VERSION 5.7 ;
  NOWIREEXTENSIONATPIN ON ;
  DIVIDERCHAR "/" ;
  BUSBITCHARS "[]" ;
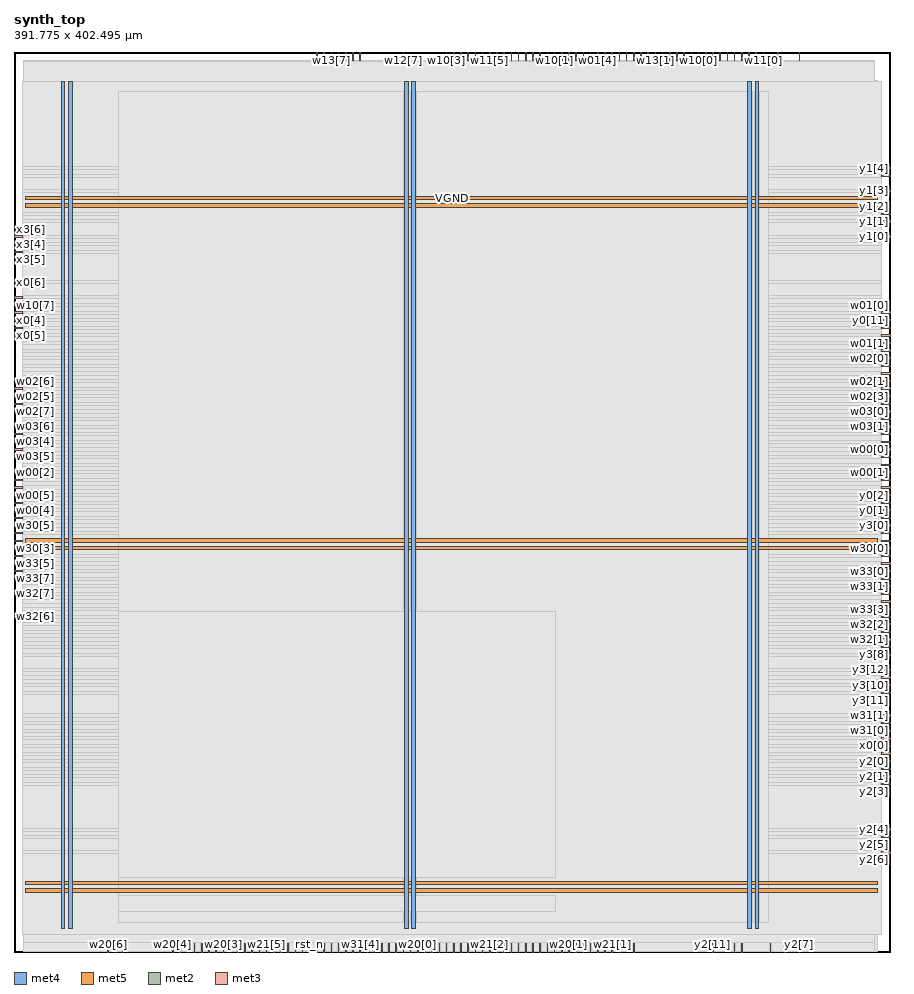
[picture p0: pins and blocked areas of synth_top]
MACRO synth_top
  CLASS BLOCK ;
  FOREIGN synth_top ;
  ORIGIN 0.000 0.000 ;
  SIZE 391.775 BY 402.495 ;
  PIN VGND
    DIRECTION INOUT ;
    USE GROUND ;
    PORT
      LAYER met4 ;
        RECT 24.340 10.640 25.940 389.200 ;
    END
    PORT
      LAYER met4 ;
        RECT 177.940 10.640 179.540 389.200 ;
    END
    PORT
      LAYER met4 ;
        RECT 331.540 10.640 333.140 389.200 ;
    END
    PORT
      LAYER met5 ;
        RECT 5.280 30.030 386.180 31.630 ;
    END
    PORT
      LAYER met5 ;
        RECT 5.280 183.210 386.180 184.810 ;
    END
    PORT
      LAYER met5 ;
        RECT 5.280 336.390 386.180 337.990 ;
    END
  END VGND
  PIN VPWR
    DIRECTION INOUT ;
    USE POWER ;
    PORT
      LAYER met4 ;
        RECT 21.040 10.640 22.640 389.200 ;
    END
    PORT
      LAYER met4 ;
        RECT 174.640 10.640 176.240 389.200 ;
    END
    PORT
      LAYER met4 ;
        RECT 328.240 10.640 329.840 389.200 ;
    END
    PORT
      LAYER met5 ;
        RECT 5.280 26.730 386.180 28.330 ;
    END
    PORT
      LAYER met5 ;
        RECT 5.280 179.910 386.180 181.510 ;
    END
    PORT
      LAYER met5 ;
        RECT 5.280 333.090 386.180 334.690 ;
    END
  END VPWR
  PIN clk
    DIRECTION INPUT ;
    USE SIGNAL ;
    ANTENNAGATEAREA 0.852000 ;
    PORT
      LAYER met2 ;
        RECT 125.670 0.000 125.950 4.000 ;
    END
  END clk
  PIN rst_n
    DIRECTION INPUT ;
    USE SIGNAL ;
    ANTENNAGATEAREA 0.159000 ;
    PORT
      LAYER met2 ;
        RECT 132.110 0.000 132.390 4.000 ;
    END
  END rst_n
  PIN w00[0]
    DIRECTION INPUT ;
    USE SIGNAL ;
    ANTENNAGATEAREA 0.196500 ;
    PORT
      LAYER met3 ;
        RECT 387.775 224.440 391.775 225.040 ;
    END
  END w00[0]
  PIN w00[1]
    DIRECTION INPUT ;
    USE SIGNAL ;
    ANTENNAGATEAREA 0.196500 ;
    PORT
      LAYER met3 ;
        RECT 387.775 214.240 391.775 214.840 ;
    END
  END w00[1]
  PIN w00[2]
    DIRECTION INPUT ;
    USE SIGNAL ;
    ANTENNAGATEAREA 0.159000 ;
    PORT
      LAYER met3 ;
        RECT 0.000 214.240 4.000 214.840 ;
    END
  END w00[2]
  PIN w00[3]
    DIRECTION INPUT ;
    USE SIGNAL ;
    ANTENNAGATEAREA 0.159000 ;
    PORT
      LAYER met3 ;
        RECT 0.000 200.640 4.000 201.240 ;
    END
  END w00[3]
  PIN w00[4]
    DIRECTION INPUT ;
    USE SIGNAL ;
    ANTENNAGATEAREA 0.159000 ;
    PORT
      LAYER met3 ;
        RECT 0.000 197.240 4.000 197.840 ;
    END
  END w00[4]
  PIN w00[5]
    DIRECTION INPUT ;
    USE SIGNAL ;
    ANTENNAGATEAREA 0.213000 ;
    PORT
      LAYER met3 ;
        RECT 0.000 204.040 4.000 204.640 ;
    END
  END w00[5]
  PIN w00[6]
    DIRECTION INPUT ;
    USE SIGNAL ;
    ANTENNAGATEAREA 0.213000 ;
    PORT
      LAYER met3 ;
        RECT 0.000 207.440 4.000 208.040 ;
    END
  END w00[6]
  PIN w00[7]
    DIRECTION INPUT ;
    USE SIGNAL ;
    ANTENNAGATEAREA 0.196500 ;
    PORT
      LAYER met3 ;
        RECT 0.000 210.840 4.000 211.440 ;
    END
  END w00[7]
  PIN w01[0]
    DIRECTION INPUT ;
    USE SIGNAL ;
    ANTENNAGATEAREA 0.213000 ;
    PORT
      LAYER met3 ;
        RECT 387.775 285.640 391.775 286.240 ;
    END
  END w01[0]
  PIN w01[1]
    DIRECTION INPUT ;
    USE SIGNAL ;
    ANTENNAGATEAREA 0.196500 ;
    PORT
      LAYER met3 ;
        RECT 387.775 272.040 391.775 272.640 ;
    END
  END w01[1]
  PIN w01[2]
    DIRECTION INPUT ;
    USE SIGNAL ;
    ANTENNAGATEAREA 0.196500 ;
    PORT
      LAYER met3 ;
        RECT 387.775 258.440 391.775 259.040 ;
    END
  END w01[2]
  PIN w01[3]
    DIRECTION INPUT ;
    USE SIGNAL ;
    ANTENNAGATEAREA 0.196500 ;
    PORT
      LAYER met2 ;
        RECT 302.770 398.495 303.050 402.495 ;
    END
  END w01[3]
  PIN w01[4]
    DIRECTION INPUT ;
    USE SIGNAL ;
    ANTENNAGATEAREA 0.196500 ;
    PORT
      LAYER met2 ;
        RECT 260.910 398.495 261.190 402.495 ;
    END
  END w01[4]
  PIN w01[5]
    DIRECTION INPUT ;
    USE SIGNAL ;
    ANTENNAGATEAREA 0.196500 ;
    PORT
      LAYER met2 ;
        RECT 277.010 398.495 277.290 402.495 ;
    END
  END w01[5]
  PIN w01[6]
    DIRECTION INPUT ;
    USE SIGNAL ;
    ANTENNAGATEAREA 0.196500 ;
    PORT
      LAYER met2 ;
        RECT 254.470 398.495 254.750 402.495 ;
    END
  END w01[6]
  PIN w01[7]
    DIRECTION INPUT ;
    USE SIGNAL ;
    ANTENNAGATEAREA 0.213000 ;
    PORT
      LAYER met2 ;
        RECT 215.830 398.495 216.110 402.495 ;
    END
  END w01[7]
  PIN w02[0]
    DIRECTION INPUT ;
    USE SIGNAL ;
    ANTENNAGATEAREA 0.213000 ;
    PORT
      LAYER met3 ;
        RECT 387.775 265.240 391.775 265.840 ;
    END
  END w02[0]
  PIN w02[1]
    DIRECTION INPUT ;
    USE SIGNAL ;
    ANTENNAGATEAREA 0.213000 ;
    PORT
      LAYER met3 ;
        RECT 387.775 255.040 391.775 255.640 ;
    END
  END w02[1]
  PIN w02[2]
    DIRECTION INPUT ;
    USE SIGNAL ;
    ANTENNAGATEAREA 0.196500 ;
    PORT
      LAYER met3 ;
        RECT 387.775 251.640 391.775 252.240 ;
    END
  END w02[2]
  PIN w02[3]
    DIRECTION INPUT ;
    USE SIGNAL ;
    ANTENNAGATEAREA 0.196500 ;
    PORT
      LAYER met3 ;
        RECT 387.775 248.240 391.775 248.840 ;
    END
  END w02[3]
  PIN w02[4]
    DIRECTION INPUT ;
    USE SIGNAL ;
    ANTENNAGATEAREA 0.213000 ;
    PORT
      LAYER met2 ;
        RECT 244.810 398.495 245.090 402.495 ;
    END
  END w02[4]
  PIN w02[5]
    DIRECTION INPUT ;
    USE SIGNAL ;
    ANTENNAGATEAREA 0.213000 ;
    PORT
      LAYER met3 ;
        RECT 0.000 248.240 4.000 248.840 ;
    END
  END w02[5]
  PIN w02[6]
    DIRECTION INPUT ;
    USE SIGNAL ;
    ANTENNAGATEAREA 0.159000 ;
    PORT
      LAYER met3 ;
        RECT 0.000 251.640 4.000 252.240 ;
    END
  END w02[6]
  PIN w02[7]
    DIRECTION INPUT ;
    USE SIGNAL ;
    ANTENNAGATEAREA 0.213000 ;
    PORT
      LAYER met3 ;
        RECT 0.000 244.840 4.000 245.440 ;
    END
  END w02[7]
  PIN w03[0]
    DIRECTION INPUT ;
    USE SIGNAL ;
    ANTENNAGATEAREA 0.213000 ;
    PORT
      LAYER met3 ;
        RECT 387.775 241.440 391.775 242.040 ;
    END
  END w03[0]
  PIN w03[1]
    DIRECTION INPUT ;
    USE SIGNAL ;
    ANTENNAGATEAREA 0.196500 ;
    PORT
      LAYER met3 ;
        RECT 387.775 238.040 391.775 238.640 ;
    END
  END w03[1]
  PIN w03[2]
    DIRECTION INPUT ;
    USE SIGNAL ;
    ANTENNAGATEAREA 0.196500 ;
    PORT
      LAYER met3 ;
        RECT 387.775 234.640 391.775 235.240 ;
    END
  END w03[2]
  PIN w03[3]
    DIRECTION INPUT ;
    USE SIGNAL ;
    ANTENNAGATEAREA 0.159000 ;
    PORT
      LAYER met3 ;
        RECT 387.775 227.840 391.775 228.440 ;
    END
  END w03[3]
  PIN w03[4]
    DIRECTION INPUT ;
    USE SIGNAL ;
    ANTENNAGATEAREA 0.213000 ;
    PORT
      LAYER met3 ;
        RECT 0.000 227.840 4.000 228.440 ;
    END
  END w03[4]
  PIN w03[5]
    DIRECTION INPUT ;
    USE SIGNAL ;
    ANTENNAGATEAREA 0.213000 ;
    PORT
      LAYER met3 ;
        RECT 0.000 224.440 4.000 225.040 ;
    END
  END w03[5]
  PIN w03[6]
    DIRECTION INPUT ;
    USE SIGNAL ;
    ANTENNAGATEAREA 0.213000 ;
    PORT
      LAYER met3 ;
        RECT 0.000 231.240 4.000 231.840 ;
    END
  END w03[6]
  PIN w03[7]
    DIRECTION INPUT ;
    USE SIGNAL ;
    ANTENNAGATEAREA 0.126000 ;
    PORT
      LAYER met3 ;
        RECT 0.000 221.040 4.000 221.640 ;
    END
  END w03[7]
  PIN w10[0]
    DIRECTION INPUT ;
    USE SIGNAL ;
    ANTENNAGATEAREA 0.196500 ;
    PORT
      LAYER met2 ;
        RECT 305.990 398.495 306.270 402.495 ;
    END
  END w10[0]
  PIN w10[1]
    DIRECTION INPUT ;
    USE SIGNAL ;
    ANTENNAGATEAREA 0.196500 ;
    PORT
      LAYER met2 ;
        RECT 241.590 398.495 241.870 402.495 ;
    END
  END w10[1]
  PIN w10[2]
    DIRECTION INPUT ;
    USE SIGNAL ;
    ANTENNAGATEAREA 0.213000 ;
    PORT
      LAYER met2 ;
        RECT 267.350 398.495 267.630 402.495 ;
    END
  END w10[2]
  PIN w10[3]
    DIRECTION INPUT ;
    USE SIGNAL ;
    ANTENNAGATEAREA 0.213000 ;
    PORT
      LAYER met2 ;
        RECT 193.290 398.495 193.570 402.495 ;
    END
  END w10[3]
  PIN w10[4]
    DIRECTION INPUT ;
    USE SIGNAL ;
    ANTENNAGATEAREA 0.213000 ;
    PORT
      LAYER met2 ;
        RECT 222.270 398.495 222.550 402.495 ;
    END
  END w10[4]
  PIN w10[5]
    DIRECTION INPUT ;
    USE SIGNAL ;
    ANTENNAGATEAREA 0.196500 ;
    PORT
      LAYER met2 ;
        RECT 219.050 398.495 219.330 402.495 ;
    END
  END w10[5]
  PIN w10[6]
    DIRECTION INPUT ;
    USE SIGNAL ;
    ANTENNAGATEAREA 0.213000 ;
    PORT
      LAYER met2 ;
        RECT 209.390 398.495 209.670 402.495 ;
    END
  END w10[6]
  PIN w10[7]
    DIRECTION INPUT ;
    USE SIGNAL ;
    ANTENNAGATEAREA 0.213000 ;
    PORT
      LAYER met3 ;
        RECT 0.000 289.040 4.000 289.640 ;
    END
  END w10[7]
  PIN w11[0]
    DIRECTION INPUT ;
    USE SIGNAL ;
    ANTENNAGATEAREA 0.126000 ;
    PORT
      LAYER met2 ;
        RECT 334.970 398.495 335.250 402.495 ;
    END
  END w11[0]
  PIN w11[1]
    DIRECTION INPUT ;
    USE SIGNAL ;
    ANTENNAGATEAREA 0.196500 ;
    PORT
      LAYER met2 ;
        RECT 296.330 398.495 296.610 402.495 ;
    END
  END w11[1]
  PIN w11[2]
    DIRECTION INPUT ;
    USE SIGNAL ;
    ANTENNAGATEAREA 0.196500 ;
    PORT
      LAYER met2 ;
        RECT 325.310 398.495 325.590 402.495 ;
    END
  END w11[2]
  PIN w11[3]
    DIRECTION INPUT ;
    USE SIGNAL ;
    ANTENNAGATEAREA 0.196500 ;
    PORT
      LAYER met2 ;
        RECT 299.550 398.495 299.830 402.495 ;
    END
  END w11[3]
  PIN w11[4]
    DIRECTION INPUT ;
    USE SIGNAL ;
    ANTENNAGATEAREA 0.196500 ;
    PORT
      LAYER met2 ;
        RECT 251.250 398.495 251.530 402.495 ;
    END
  END w11[4]
  PIN w11[5]
    DIRECTION INPUT ;
    USE SIGNAL ;
    ANTENNAGATEAREA 0.196500 ;
    PORT
      LAYER met2 ;
        RECT 212.610 398.495 212.890 402.495 ;
    END
  END w11[5]
  PIN w11[6]
    DIRECTION INPUT ;
    USE SIGNAL ;
    ANTENNAGATEAREA 0.196500 ;
    PORT
      LAYER met2 ;
        RECT 231.930 398.495 232.210 402.495 ;
    END
  END w11[6]
  PIN w11[7]
    DIRECTION INPUT ;
    USE SIGNAL ;
    ANTENNAGATEAREA 0.213000 ;
    PORT
      LAYER met2 ;
        RECT 228.710 398.495 228.990 402.495 ;
    END
  END w11[7]
  PIN w12[0]
    DIRECTION INPUT ;
    USE SIGNAL ;
    ANTENNAGATEAREA 0.126000 ;
    PORT
      LAYER met2 ;
        RECT 312.430 398.495 312.710 402.495 ;
    END
  END w12[0]
  PIN w12[1]
    DIRECTION INPUT ;
    USE SIGNAL ;
    ANTENNAGATEAREA 0.126000 ;
    PORT
      LAYER met2 ;
        RECT 248.030 398.495 248.310 402.495 ;
    END
  END w12[1]
  PIN w12[2]
    DIRECTION INPUT ;
    USE SIGNAL ;
    ANTENNAGATEAREA 0.196500 ;
    PORT
      LAYER met2 ;
        RECT 264.130 398.495 264.410 402.495 ;
    END
  END w12[2]
  PIN w12[3]
    DIRECTION INPUT ;
    USE SIGNAL ;
    ANTENNAGATEAREA 0.213000 ;
    PORT
      LAYER met2 ;
        RECT 270.570 398.495 270.850 402.495 ;
    END
  END w12[3]
  PIN w12[4]
    DIRECTION INPUT ;
    USE SIGNAL ;
    ANTENNAGATEAREA 0.213000 ;
    PORT
      LAYER met2 ;
        RECT 257.690 398.495 257.970 402.495 ;
    END
  END w12[4]
  PIN w12[5]
    DIRECTION INPUT ;
    USE SIGNAL ;
    ANTENNAGATEAREA 0.196500 ;
    PORT
      LAYER met2 ;
        RECT 199.730 398.495 200.010 402.495 ;
    END
  END w12[5]
  PIN w12[6]
    DIRECTION INPUT ;
    USE SIGNAL ;
    ANTENNAGATEAREA 0.196500 ;
    PORT
      LAYER met2 ;
        RECT 225.490 398.495 225.770 402.495 ;
    END
  END w12[6]
  PIN w12[7]
    DIRECTION INPUT ;
    USE SIGNAL ;
    ANTENNAGATEAREA 0.196500 ;
    PORT
      LAYER met2 ;
        RECT 173.970 398.495 174.250 402.495 ;
    END
  END w12[7]
  PIN w13[0]
    DIRECTION INPUT ;
    USE SIGNAL ;
    ANTENNAGATEAREA 0.213000 ;
    PORT
      LAYER met2 ;
        RECT 289.890 398.495 290.170 402.495 ;
    END
  END w13[0]
  PIN w13[1]
    DIRECTION INPUT ;
    USE SIGNAL ;
    ANTENNAGATEAREA 0.196500 ;
    PORT
      LAYER met2 ;
        RECT 286.670 398.495 286.950 402.495 ;
    END
  END w13[1]
  PIN w13[2]
    DIRECTION INPUT ;
    USE SIGNAL ;
    ANTENNAGATEAREA 0.196500 ;
    PORT
      LAYER met2 ;
        RECT 202.950 398.495 203.230 402.495 ;
    END
  END w13[2]
  PIN w13[3]
    DIRECTION INPUT ;
    USE SIGNAL ;
    ANTENNAGATEAREA 0.213000 ;
    PORT
      LAYER met2 ;
        RECT 283.450 398.495 283.730 402.495 ;
    END
  END w13[3]
  PIN w13[4]
    DIRECTION INPUT ;
    USE SIGNAL ;
    ANTENNAGATEAREA 0.196500 ;
    PORT
      LAYER met2 ;
        RECT 273.790 398.495 274.070 402.495 ;
    END
  END w13[4]
  PIN w13[5]
    DIRECTION INPUT ;
    USE SIGNAL ;
    ANTENNAGATEAREA 0.196500 ;
    PORT
      LAYER met2 ;
        RECT 235.150 398.495 235.430 402.495 ;
    END
  END w13[5]
  PIN w13[6]
    DIRECTION INPUT ;
    USE SIGNAL ;
    ANTENNAGATEAREA 0.213000 ;
    PORT
      LAYER met2 ;
        RECT 196.510 398.495 196.790 402.495 ;
    END
  END w13[6]
  PIN w13[7]
    DIRECTION INPUT ;
    USE SIGNAL ;
    ANTENNAGATEAREA 0.213000 ;
    PORT
      LAYER met2 ;
        RECT 141.770 398.495 142.050 402.495 ;
    END
  END w13[7]
  PIN w20[0]
    DIRECTION INPUT ;
    USE SIGNAL ;
    ANTENNAGATEAREA 0.213000 ;
    PORT
      LAYER met2 ;
        RECT 180.410 0.000 180.690 4.000 ;
    END
  END w20[0]
  PIN w20[1]
    DIRECTION INPUT ;
    USE SIGNAL ;
    ANTENNAGATEAREA 0.196500 ;
    PORT
      LAYER met2 ;
        RECT 248.030 0.000 248.310 4.000 ;
    END
  END w20[1]
  PIN w20[2]
    DIRECTION INPUT ;
    USE SIGNAL ;
    ANTENNAGATEAREA 0.213000 ;
    PORT
      LAYER met2 ;
        RECT 119.230 0.000 119.510 4.000 ;
    END
  END w20[2]
  PIN w20[3]
    DIRECTION INPUT ;
    USE SIGNAL ;
    ANTENNAGATEAREA 0.159000 ;
    PORT
      LAYER met2 ;
        RECT 93.470 0.000 93.750 4.000 ;
    END
  END w20[3]
  PIN w20[4]
    DIRECTION INPUT ;
    USE SIGNAL ;
    ANTENNAGATEAREA 0.213000 ;
    PORT
      LAYER met2 ;
        RECT 70.930 0.000 71.210 4.000 ;
    END
  END w20[4]
  PIN w20[5]
    DIRECTION INPUT ;
    USE SIGNAL ;
    ANTENNAGATEAREA 0.213000 ;
    PORT
      LAYER met2 ;
        RECT 45.170 0.000 45.450 4.000 ;
    END
  END w20[5]
  PIN w20[6]
    DIRECTION INPUT ;
    USE SIGNAL ;
    ANTENNAGATEAREA 0.159000 ;
    PORT
      LAYER met2 ;
        RECT 41.950 0.000 42.230 4.000 ;
    END
  END w20[6]
  PIN w20[7]
    DIRECTION INPUT ;
    USE SIGNAL ;
    ANTENNAGATEAREA 0.213000 ;
    PORT
      LAYER met2 ;
        RECT 48.390 0.000 48.670 4.000 ;
    END
  END w20[7]
  PIN w21[0]
    DIRECTION INPUT ;
    USE SIGNAL ;
    ANTENNAGATEAREA 0.213000 ;
    PORT
      LAYER met2 ;
        RECT 277.010 0.000 277.290 4.000 ;
    END
  END w21[0]
  PIN w21[1]
    DIRECTION INPUT ;
    USE SIGNAL ;
    ANTENNAGATEAREA 0.196500 ;
    PORT
      LAYER met2 ;
        RECT 267.350 0.000 267.630 4.000 ;
    END
  END w21[1]
  PIN w21[2]
    DIRECTION INPUT ;
    USE SIGNAL ;
    ANTENNAGATEAREA 0.213000 ;
    PORT
      LAYER met2 ;
        RECT 212.610 0.000 212.890 4.000 ;
    END
  END w21[2]
  PIN w21[3]
    DIRECTION INPUT ;
    USE SIGNAL ;
    ANTENNAGATEAREA 0.196500 ;
    PORT
      LAYER met2 ;
        RECT 173.970 0.000 174.250 4.000 ;
    END
  END w21[3]
  PIN w21[4]
    DIRECTION INPUT ;
    USE SIGNAL ;
    ANTENNAGATEAREA 0.196500 ;
    PORT
      LAYER met2 ;
        RECT 141.770 0.000 142.050 4.000 ;
    END
  END w21[4]
  PIN w21[5]
    DIRECTION INPUT ;
    USE SIGNAL ;
    ANTENNAGATEAREA 0.196500 ;
    PORT
      LAYER met2 ;
        RECT 112.790 0.000 113.070 4.000 ;
    END
  END w21[5]
  PIN w21[6]
    DIRECTION INPUT ;
    USE SIGNAL ;
    ANTENNAGATEAREA 0.196500 ;
    PORT
      LAYER met2 ;
        RECT 99.910 0.000 100.190 4.000 ;
    END
  END w21[6]
  PIN w21[7]
    DIRECTION INPUT ;
    USE SIGNAL ;
    ANTENNAGATEAREA 0.196500 ;
    PORT
      LAYER met2 ;
        RECT 116.010 0.000 116.290 4.000 ;
    END
  END w21[7]
  PIN w22[0]
    DIRECTION INPUT ;
    USE SIGNAL ;
    ANTENNAGATEAREA 0.213000 ;
    PORT
      LAYER met2 ;
        RECT 235.150 0.000 235.430 4.000 ;
    END
  END w22[0]
  PIN w22[1]
    DIRECTION INPUT ;
    USE SIGNAL ;
    ANTENNAGATEAREA 0.213000 ;
    PORT
      LAYER met2 ;
        RECT 206.170 0.000 206.450 4.000 ;
    END
  END w22[1]
  PIN w22[2]
    DIRECTION INPUT ;
    USE SIGNAL ;
    ANTENNAGATEAREA 0.196500 ;
    PORT
      LAYER met2 ;
        RECT 251.250 0.000 251.530 4.000 ;
    END
  END w22[2]
  PIN w22[3]
    DIRECTION INPUT ;
    USE SIGNAL ;
    ANTENNAGATEAREA 0.196500 ;
    PORT
      LAYER met2 ;
        RECT 144.990 0.000 145.270 4.000 ;
    END
  END w22[3]
  PIN w22[4]
    DIRECTION INPUT ;
    USE SIGNAL ;
    ANTENNAGATEAREA 0.196500 ;
    PORT
      LAYER met2 ;
        RECT 231.930 0.000 232.210 4.000 ;
    END
  END w22[4]
  PIN w22[5]
    DIRECTION INPUT ;
    USE SIGNAL ;
    ANTENNAGATEAREA 0.126000 ;
    PORT
      LAYER met2 ;
        RECT 106.350 0.000 106.630 4.000 ;
    END
  END w22[5]
  PIN w22[6]
    DIRECTION INPUT ;
    USE SIGNAL ;
    ANTENNAGATEAREA 0.196500 ;
    PORT
      LAYER met2 ;
        RECT 87.030 0.000 87.310 4.000 ;
    END
  END w22[6]
  PIN w22[7]
    DIRECTION INPUT ;
    USE SIGNAL ;
    ANTENNAGATEAREA 0.196500 ;
    PORT
      LAYER met2 ;
        RECT 77.370 0.000 77.650 4.000 ;
    END
  END w22[7]
  PIN w23[0]
    DIRECTION INPUT ;
    USE SIGNAL ;
    ANTENNAGATEAREA 0.159000 ;
    PORT
      LAYER met2 ;
        RECT 190.070 0.000 190.350 4.000 ;
    END
  END w23[0]
  PIN w23[1]
    DIRECTION INPUT ;
    USE SIGNAL ;
    ANTENNAGATEAREA 0.196500 ;
    PORT
      LAYER met2 ;
        RECT 183.630 0.000 183.910 4.000 ;
    END
  END w23[1]
  PIN w23[2]
    DIRECTION INPUT ;
    USE SIGNAL ;
    ANTENNAGATEAREA 0.126000 ;
    PORT
      LAYER met2 ;
        RECT 148.210 0.000 148.490 4.000 ;
    END
  END w23[2]
  PIN w23[3]
    DIRECTION INPUT ;
    USE SIGNAL ;
    ANTENNAGATEAREA 0.213000 ;
    PORT
      LAYER met2 ;
        RECT 128.890 0.000 129.170 4.000 ;
    END
  END w23[3]
  PIN w23[4]
    DIRECTION INPUT ;
    USE SIGNAL ;
    ANTENNAGATEAREA 0.196500 ;
    PORT
      LAYER met2 ;
        RECT 264.130 0.000 264.410 4.000 ;
    END
  END w23[4]
  PIN w23[5]
    DIRECTION INPUT ;
    USE SIGNAL ;
    ANTENNAGATEAREA 0.196500 ;
    PORT
      LAYER met2 ;
        RECT 83.810 0.000 84.090 4.000 ;
    END
  END w23[5]
  PIN w23[6]
    DIRECTION INPUT ;
    USE SIGNAL ;
    ANTENNAGATEAREA 0.126000 ;
    PORT
      LAYER met2 ;
        RECT 74.150 0.000 74.430 4.000 ;
    END
  END w23[6]
  PIN w23[7]
    DIRECTION INPUT ;
    USE SIGNAL ;
    ANTENNAGATEAREA 0.196500 ;
    PORT
      LAYER met2 ;
        RECT 80.590 0.000 80.870 4.000 ;
    END
  END w23[7]
  PIN w30[0]
    DIRECTION INPUT ;
    USE SIGNAL ;
    ANTENNAGATEAREA 0.213000 ;
    PORT
      LAYER met3 ;
        RECT 387.775 180.240 391.775 180.840 ;
    END
  END w30[0]
  PIN w30[1]
    DIRECTION INPUT ;
    USE SIGNAL ;
    ANTENNAGATEAREA 0.196500 ;
    PORT
      LAYER met3 ;
        RECT 387.775 200.640 391.775 201.240 ;
    END
  END w30[1]
  PIN w30[2]
    DIRECTION INPUT ;
    USE SIGNAL ;
    ANTENNAGATEAREA 0.213000 ;
    PORT
      LAYER met3 ;
        RECT 387.775 183.640 391.775 184.240 ;
    END
  END w30[2]
  PIN w30[3]
    DIRECTION INPUT ;
    USE SIGNAL ;
    ANTENNAGATEAREA 0.159000 ;
    PORT
      LAYER met3 ;
        RECT 0.000 180.240 4.000 180.840 ;
    END
  END w30[3]
  PIN w30[4]
    DIRECTION INPUT ;
    USE SIGNAL ;
    ANTENNAGATEAREA 0.159000 ;
    PORT
      LAYER met3 ;
        RECT 0.000 183.640 4.000 184.240 ;
    END
  END w30[4]
  PIN w30[5]
    DIRECTION INPUT ;
    USE SIGNAL ;
    ANTENNAGATEAREA 0.213000 ;
    PORT
      LAYER met3 ;
        RECT 0.000 190.440 4.000 191.040 ;
    END
  END w30[5]
  PIN w30[6]
    DIRECTION INPUT ;
    USE SIGNAL ;
    ANTENNAGATEAREA 0.159000 ;
    PORT
      LAYER met3 ;
        RECT 0.000 193.840 4.000 194.440 ;
    END
  END w30[6]
  PIN w30[7]
    DIRECTION INPUT ;
    USE SIGNAL ;
    ANTENNAGATEAREA 0.213000 ;
    PORT
      LAYER met3 ;
        RECT 0.000 187.040 4.000 187.640 ;
    END
  END w30[7]
  PIN w31[0]
    DIRECTION INPUT ;
    USE SIGNAL ;
    ANTENNAGATEAREA 0.213000 ;
    PORT
      LAYER met3 ;
        RECT 387.775 98.640 391.775 99.240 ;
    END
  END w31[0]
  PIN w31[1]
    DIRECTION INPUT ;
    USE SIGNAL ;
    ANTENNAGATEAREA 0.196500 ;
    PORT
      LAYER met3 ;
        RECT 387.775 102.040 391.775 102.640 ;
    END
  END w31[1]
  PIN w31[2]
    DIRECTION INPUT ;
    USE SIGNAL ;
    ANTENNAGATEAREA 0.196500 ;
    PORT
      LAYER met2 ;
        RECT 254.470 0.000 254.750 4.000 ;
    END
  END w31[2]
  PIN w31[3]
    DIRECTION INPUT ;
    USE SIGNAL ;
    ANTENNAGATEAREA 0.126000 ;
    PORT
      LAYER met2 ;
        RECT 209.390 0.000 209.670 4.000 ;
    END
  END w31[3]
  PIN w31[4]
    DIRECTION INPUT ;
    USE SIGNAL ;
    ANTENNAGATEAREA 0.213000 ;
    PORT
      LAYER met2 ;
        RECT 154.650 0.000 154.930 4.000 ;
    END
  END w31[4]
  PIN w31[5]
    DIRECTION INPUT ;
    USE SIGNAL ;
    ANTENNAGATEAREA 0.126000 ;
    PORT
      LAYER met2 ;
        RECT 151.430 0.000 151.710 4.000 ;
    END
  END w31[5]
  PIN w31[6]
    DIRECTION INPUT ;
    USE SIGNAL ;
    ANTENNAGATEAREA 0.213000 ;
    PORT
      LAYER met2 ;
        RECT 109.570 0.000 109.850 4.000 ;
    END
  END w31[6]
  PIN w31[7]
    DIRECTION INPUT ;
    USE SIGNAL ;
    ANTENNAGATEAREA 0.213000 ;
    PORT
      LAYER met2 ;
        RECT 122.450 0.000 122.730 4.000 ;
    END
  END w31[7]
  PIN w32[0]
    DIRECTION INPUT ;
    USE SIGNAL ;
    ANTENNAGATEAREA 0.213000 ;
    PORT
      LAYER met3 ;
        RECT 387.775 122.440 391.775 123.040 ;
    END
  END w32[0]
  PIN w32[1]
    DIRECTION INPUT ;
    USE SIGNAL ;
    ANTENNAGATEAREA 0.126000 ;
    PORT
      LAYER met3 ;
        RECT 387.775 139.440 391.775 140.040 ;
    END
  END w32[1]
  PIN w32[2]
    DIRECTION INPUT ;
    USE SIGNAL ;
    ANTENNAGATEAREA 0.213000 ;
    PORT
      LAYER met3 ;
        RECT 387.775 142.840 391.775 143.440 ;
    END
  END w32[2]
  PIN w32[3]
    DIRECTION INPUT ;
    USE SIGNAL ;
    ANTENNAGATEAREA 0.213000 ;
    PORT
      LAYER met2 ;
        RECT 170.750 0.000 171.030 4.000 ;
    END
  END w32[3]
  PIN w32[4]
    DIRECTION INPUT ;
    USE SIGNAL ;
    ANTENNAGATEAREA 0.213000 ;
    PORT
      LAYER met2 ;
        RECT 222.270 0.000 222.550 4.000 ;
    END
  END w32[4]
  PIN w32[5]
    DIRECTION INPUT ;
    USE SIGNAL ;
    ANTENNAGATEAREA 0.159000 ;
    PORT
      LAYER met2 ;
        RECT 103.130 0.000 103.410 4.000 ;
    END
  END w32[5]
  PIN w32[6]
    DIRECTION INPUT ;
    USE SIGNAL ;
    ANTENNAGATEAREA 0.213000 ;
    PORT
      LAYER met3 ;
        RECT 0.000 149.640 4.000 150.240 ;
    END
  END w32[6]
  PIN w32[7]
    DIRECTION INPUT ;
    USE SIGNAL ;
    ANTENNAGATEAREA 0.213000 ;
    PORT
      LAYER met3 ;
        RECT 0.000 159.840 4.000 160.440 ;
    END
  END w32[7]
  PIN w33[0]
    DIRECTION INPUT ;
    USE SIGNAL ;
    ANTENNAGATEAREA 0.213000 ;
    PORT
      LAYER met3 ;
        RECT 387.775 170.040 391.775 170.640 ;
    END
  END w33[0]
  PIN w33[1]
    DIRECTION INPUT ;
    USE SIGNAL ;
    ANTENNAGATEAREA 0.196500 ;
    PORT
      LAYER met3 ;
        RECT 387.775 163.240 391.775 163.840 ;
    END
  END w33[1]
  PIN w33[2]
    DIRECTION INPUT ;
    USE SIGNAL ;
    ANTENNAGATEAREA 0.196500 ;
    PORT
      LAYER met3 ;
        RECT 387.775 149.640 391.775 150.240 ;
    END
  END w33[2]
  PIN w33[3]
    DIRECTION INPUT ;
    USE SIGNAL ;
    ANTENNAGATEAREA 0.159000 ;
    PORT
      LAYER met3 ;
        RECT 387.775 153.040 391.775 153.640 ;
    END
  END w33[3]
  PIN w33[4]
    DIRECTION INPUT ;
    USE SIGNAL ;
    ANTENNAGATEAREA 0.126000 ;
    PORT
      LAYER met3 ;
        RECT 387.775 159.840 391.775 160.440 ;
    END
  END w33[4]
  PIN w33[5]
    DIRECTION INPUT ;
    USE SIGNAL ;
    ANTENNAGATEAREA 0.196500 ;
    PORT
      LAYER met3 ;
        RECT 0.000 176.840 4.000 177.440 ;
    END
  END w33[5]
  PIN w33[6]
    DIRECTION INPUT ;
    USE SIGNAL ;
    ANTENNAGATEAREA 0.196500 ;
    PORT
      LAYER met3 ;
        RECT 0.000 173.440 4.000 174.040 ;
    END
  END w33[6]
  PIN w33[7]
    DIRECTION INPUT ;
    USE SIGNAL ;
    ANTENNAGATEAREA 0.196500 ;
    PORT
      LAYER met3 ;
        RECT 0.000 170.040 4.000 170.640 ;
    END
  END w33[7]
  PIN x0[0]
    DIRECTION INPUT ;
    USE SIGNAL ;
    ANTENNAGATEAREA 0.742500 ;
    PORT
      LAYER met3 ;
        RECT 387.775 91.840 391.775 92.440 ;
    END
  END x0[0]
  PIN x0[1]
    DIRECTION INPUT ;
    USE SIGNAL ;
    ANTENNAGATEAREA 0.495000 ;
    PORT
      LAYER met2 ;
        RECT 270.570 0.000 270.850 4.000 ;
    END
  END x0[1]
  PIN x0[2]
    DIRECTION INPUT ;
    USE SIGNAL ;
    ANTENNAGATEAREA 0.213000 ;
    PORT
      LAYER met3 ;
        RECT 0.000 292.440 4.000 293.040 ;
    END
  END x0[2]
  PIN x0[3]
    DIRECTION INPUT ;
    USE SIGNAL ;
    ANTENNAGATEAREA 0.196500 ;
    PORT
      LAYER met3 ;
        RECT 0.000 285.640 4.000 286.240 ;
    END
  END x0[3]
  PIN x0[4]
    DIRECTION INPUT ;
    USE SIGNAL ;
    ANTENNAGATEAREA 0.196500 ;
    PORT
      LAYER met3 ;
        RECT 0.000 282.240 4.000 282.840 ;
    END
  END x0[4]
  PIN x0[5]
    DIRECTION INPUT ;
    USE SIGNAL ;
    ANTENNAGATEAREA 0.196500 ;
    PORT
      LAYER met3 ;
        RECT 0.000 278.840 4.000 279.440 ;
    END
  END x0[5]
  PIN x0[6]
    DIRECTION INPUT ;
    USE SIGNAL ;
    ANTENNAGATEAREA 0.126000 ;
    PORT
      LAYER met3 ;
        RECT 0.000 299.240 4.000 299.840 ;
    END
  END x0[6]
  PIN x0[7]
    DIRECTION INPUT ;
    USE SIGNAL ;
    ANTENNAGATEAREA 0.213000 ;
    PORT
      LAYER met3 ;
        RECT 0.000 275.440 4.000 276.040 ;
    END
  END x0[7]
  PIN x1[0]
    DIRECTION INPUT ;
    USE SIGNAL ;
    ANTENNAGATEAREA 0.196500 ;
    PORT
      LAYER met2 ;
        RECT 328.530 398.495 328.810 402.495 ;
    END
  END x1[0]
  PIN x1[1]
    DIRECTION INPUT ;
    USE SIGNAL ;
    ANTENNAGATEAREA 0.196500 ;
    PORT
      LAYER met2 ;
        RECT 322.090 398.495 322.370 402.495 ;
    END
  END x1[1]
  PIN x1[2]
    DIRECTION INPUT ;
    USE SIGNAL ;
    ANTENNAGATEAREA 0.196500 ;
    PORT
      LAYER met2 ;
        RECT 331.750 398.495 332.030 402.495 ;
    END
  END x1[2]
  PIN x1[3]
    DIRECTION INPUT ;
    USE SIGNAL ;
    ANTENNAGATEAREA 0.159000 ;
    PORT
      LAYER met2 ;
        RECT 167.530 0.000 167.810 4.000 ;
    END
  END x1[3]
  PIN x1[4]
    DIRECTION INPUT ;
    USE SIGNAL ;
    ANTENNAGATEAREA 0.196500 ;
    PORT
      LAYER met2 ;
        RECT 219.050 0.000 219.330 4.000 ;
    END
  END x1[4]
  PIN x1[5]
    DIRECTION INPUT ;
    USE SIGNAL ;
    ANTENNAGATEAREA 0.196500 ;
    PORT
      LAYER met2 ;
        RECT 257.690 0.000 257.970 4.000 ;
    END
  END x1[5]
  PIN x1[6]
    DIRECTION INPUT ;
    USE SIGNAL ;
    ANTENNAGATEAREA 0.196500 ;
    PORT
      LAYER met2 ;
        RECT 96.690 0.000 96.970 4.000 ;
    END
  END x1[6]
  PIN x1[7]
    DIRECTION INPUT ;
    USE SIGNAL ;
    ANTENNAGATEAREA 0.196500 ;
    PORT
      LAYER met2 ;
        RECT 196.510 0.000 196.790 4.000 ;
    END
  END x1[7]
  PIN x2[0]
    DIRECTION INPUT ;
    USE SIGNAL ;
    ANTENNAGATEAREA 0.213000 ;
    PORT
      LAYER met2 ;
        RECT 157.870 0.000 158.150 4.000 ;
    END
  END x2[0]
  PIN x2[1]
    DIRECTION INPUT ;
    USE SIGNAL ;
    ANTENNAGATEAREA 0.213000 ;
    PORT
      LAYER met2 ;
        RECT 90.250 0.000 90.530 4.000 ;
    END
  END x2[1]
  PIN x2[2]
    DIRECTION INPUT ;
    USE SIGNAL ;
    ANTENNAGATEAREA 0.196500 ;
    PORT
      LAYER met2 ;
        RECT 238.370 0.000 238.650 4.000 ;
    END
  END x2[2]
  PIN x2[3]
    DIRECTION INPUT ;
    USE SIGNAL ;
    ANTENNAGATEAREA 0.159000 ;
    PORT
      LAYER met2 ;
        RECT 215.830 0.000 216.110 4.000 ;
    END
  END x2[3]
  PIN x2[4]
    DIRECTION INPUT ;
    USE SIGNAL ;
    ANTENNAGATEAREA 0.196500 ;
    PORT
      LAYER met2 ;
        RECT 244.810 0.000 245.090 4.000 ;
    END
  END x2[4]
  PIN x2[5]
    DIRECTION INPUT ;
    USE SIGNAL ;
    ANTENNAGATEAREA 0.196500 ;
    PORT
      LAYER met2 ;
        RECT 260.910 0.000 261.190 4.000 ;
    END
  END x2[5]
  PIN x2[6]
    DIRECTION INPUT ;
    USE SIGNAL ;
    ANTENNAGATEAREA 0.196500 ;
    PORT
      LAYER met2 ;
        RECT 225.490 0.000 225.770 4.000 ;
    END
  END x2[6]
  PIN x2[7]
    DIRECTION INPUT ;
    USE SIGNAL ;
    ANTENNAGATEAREA 0.426000 ;
    PORT
      LAYER met2 ;
        RECT 228.710 0.000 228.990 4.000 ;
    END
  END x2[7]
  PIN x3[0]
    DIRECTION INPUT ;
    USE SIGNAL ;
    ANTENNAGATEAREA 0.196500 ;
    PORT
      LAYER met3 ;
        RECT 387.775 88.440 391.775 89.040 ;
    END
  END x3[0]
  PIN x3[1]
    DIRECTION INPUT ;
    USE SIGNAL ;
    ANTENNAGATEAREA 0.196500 ;
    PORT
      LAYER met3 ;
        RECT 387.775 95.240 391.775 95.840 ;
    END
  END x3[1]
  PIN x3[2]
    DIRECTION INPUT ;
    USE SIGNAL ;
    ANTENNAGATEAREA 0.213000 ;
    PORT
      LAYER met3 ;
        RECT 387.775 105.440 391.775 106.040 ;
    END
  END x3[2]
  PIN x3[3]
    DIRECTION INPUT ;
    USE SIGNAL ;
    ANTENNAGATEAREA 0.196500 ;
    PORT
      LAYER met2 ;
        RECT 241.590 0.000 241.870 4.000 ;
    END
  END x3[3]
  PIN x3[4]
    DIRECTION INPUT ;
    USE SIGNAL ;
    ANTENNAGATEAREA 0.196500 ;
    PORT
      LAYER met3 ;
        RECT 0.000 316.240 4.000 316.840 ;
    END
  END x3[4]
  PIN x3[5]
    DIRECTION INPUT ;
    USE SIGNAL ;
    ANTENNAGATEAREA 0.196500 ;
    PORT
      LAYER met3 ;
        RECT 0.000 312.840 4.000 313.440 ;
    END
  END x3[5]
  PIN x3[6]
    DIRECTION INPUT ;
    USE SIGNAL ;
    ANTENNAGATEAREA 0.213000 ;
    PORT
      LAYER met3 ;
        RECT 0.000 319.640 4.000 320.240 ;
    END
  END x3[6]
  PIN x3[7]
    DIRECTION INPUT ;
    USE SIGNAL ;
    ANTENNAGATEAREA 0.213000 ;
    PORT
      LAYER met2 ;
        RECT 138.550 0.000 138.830 4.000 ;
    END
  END x3[7]
  PIN y0[0]
    DIRECTION OUTPUT ;
    USE SIGNAL ;
    ANTENNADIFFAREA 0.445500 ;
    PORT
      LAYER met3 ;
        RECT 387.775 217.640 391.775 218.240 ;
    END
  END y0[0]
  PIN y0[10]
    DIRECTION OUTPUT ;
    USE SIGNAL ;
    ANTENNADIFFAREA 0.445500 ;
    PORT
      LAYER met3 ;
        RECT 387.775 278.840 391.775 279.440 ;
    END
  END y0[10]
  PIN y0[11]
    DIRECTION OUTPUT ;
    USE SIGNAL ;
    ANTENNADIFFAREA 0.445500 ;
    PORT
      LAYER met3 ;
        RECT 387.775 282.240 391.775 282.840 ;
    END
  END y0[11]
  PIN y0[12]
    DIRECTION OUTPUT ;
    USE SIGNAL ;
    ANTENNADIFFAREA 0.445500 ;
    PORT
      LAYER met3 ;
        RECT 387.775 275.440 391.775 276.040 ;
    END
  END y0[12]
  PIN y0[13]
    DIRECTION OUTPUT ;
    USE SIGNAL ;
    ANTENNADIFFAREA 0.445500 ;
    PORT
      LAYER met2 ;
        RECT 238.370 398.495 238.650 402.495 ;
    END
  END y0[13]
  PIN y0[14]
    DIRECTION OUTPUT ;
    USE SIGNAL ;
    ANTENNADIFFAREA 0.445500 ;
    PORT
      LAYER met2 ;
        RECT 148.210 398.495 148.490 402.495 ;
    END
  END y0[14]
  PIN y0[15]
    DIRECTION OUTPUT ;
    USE SIGNAL ;
    ANTENNADIFFAREA 0.445500 ;
    PORT
      LAYER met2 ;
        RECT 144.990 398.495 145.270 402.495 ;
    END
  END y0[15]
  PIN y0[16]
    DIRECTION OUTPUT ;
    USE SIGNAL ;
    ANTENNADIFFAREA 0.445500 ;
    PORT
      LAYER met2 ;
        RECT 135.330 398.495 135.610 402.495 ;
    END
  END y0[16]
  PIN y0[1]
    DIRECTION OUTPUT ;
    USE SIGNAL ;
    ANTENNADIFFAREA 0.445500 ;
    PORT
      LAYER met3 ;
        RECT 387.775 197.240 391.775 197.840 ;
    END
  END y0[1]
  PIN y0[2]
    DIRECTION OUTPUT ;
    USE SIGNAL ;
    ANTENNADIFFAREA 0.445500 ;
    PORT
      LAYER met3 ;
        RECT 387.775 204.040 391.775 204.640 ;
    END
  END y0[2]
  PIN y0[3]
    DIRECTION OUTPUT ;
    USE SIGNAL ;
    ANTENNADIFFAREA 0.445500 ;
    PORT
      LAYER met3 ;
        RECT 387.775 207.440 391.775 208.040 ;
    END
  END y0[3]
  PIN y0[4]
    DIRECTION OUTPUT ;
    USE SIGNAL ;
    ANTENNADIFFAREA 0.445500 ;
    PORT
      LAYER met3 ;
        RECT 387.775 210.840 391.775 211.440 ;
    END
  END y0[4]
  PIN y0[5]
    DIRECTION OUTPUT ;
    USE SIGNAL ;
    ANTENNADIFFAREA 0.445500 ;
    PORT
      LAYER met3 ;
        RECT 387.775 221.040 391.775 221.640 ;
    END
  END y0[5]
  PIN y0[6]
    DIRECTION OUTPUT ;
    USE SIGNAL ;
    ANTENNADIFFAREA 0.445500 ;
    PORT
      LAYER met3 ;
        RECT 387.775 231.240 391.775 231.840 ;
    END
  END y0[6]
  PIN y0[7]
    DIRECTION OUTPUT ;
    USE SIGNAL ;
    ANTENNADIFFAREA 0.445500 ;
    PORT
      LAYER met3 ;
        RECT 387.775 244.840 391.775 245.440 ;
    END
  END y0[7]
  PIN y0[8]
    DIRECTION OUTPUT ;
    USE SIGNAL ;
    ANTENNADIFFAREA 0.445500 ;
    PORT
      LAYER met3 ;
        RECT 387.775 261.840 391.775 262.440 ;
    END
  END y0[8]
  PIN y0[9]
    DIRECTION OUTPUT ;
    USE SIGNAL ;
    ANTENNADIFFAREA 0.445500 ;
    PORT
      LAYER met3 ;
        RECT 387.775 268.640 391.775 269.240 ;
    END
  END y0[9]
  PIN y1[0]
    DIRECTION OUTPUT ;
    USE SIGNAL ;
    ANTENNADIFFAREA 0.445500 ;
    PORT
      LAYER met3 ;
        RECT 387.775 319.640 391.775 320.240 ;
    END
  END y1[0]
  PIN y1[10]
    DIRECTION OUTPUT ;
    USE SIGNAL ;
    ANTENNADIFFAREA 0.445500 ;
    PORT
      LAYER met2 ;
        RECT 309.210 398.495 309.490 402.495 ;
    END
  END y1[10]
  PIN y1[11]
    DIRECTION OUTPUT ;
    USE SIGNAL ;
    ANTENNADIFFAREA 0.445500 ;
    PORT
      LAYER met2 ;
        RECT 293.110 398.495 293.390 402.495 ;
    END
  END y1[11]
  PIN y1[12]
    DIRECTION OUTPUT ;
    USE SIGNAL ;
    ANTENNADIFFAREA 0.445500 ;
    PORT
      LAYER met2 ;
        RECT 280.230 398.495 280.510 402.495 ;
    END
  END y1[12]
  PIN y1[13]
    DIRECTION OUTPUT ;
    USE SIGNAL ;
    ANTENNADIFFAREA 0.445500 ;
    PORT
      LAYER met2 ;
        RECT 206.170 398.495 206.450 402.495 ;
    END
  END y1[13]
  PIN y1[14]
    DIRECTION OUTPUT ;
    USE SIGNAL ;
    ANTENNADIFFAREA 0.445500 ;
    PORT
      LAYER met2 ;
        RECT 154.650 398.495 154.930 402.495 ;
    END
  END y1[14]
  PIN y1[15]
    DIRECTION OUTPUT ;
    USE SIGNAL ;
    ANTENNADIFFAREA 0.445500 ;
    PORT
      LAYER met2 ;
        RECT 151.430 398.495 151.710 402.495 ;
    END
  END y1[15]
  PIN y1[16]
    DIRECTION OUTPUT ;
    USE SIGNAL ;
    ANTENNADIFFAREA 0.445500 ;
    PORT
      LAYER met2 ;
        RECT 138.550 398.495 138.830 402.495 ;
    END
  END y1[16]
  PIN y1[1]
    DIRECTION OUTPUT ;
    USE SIGNAL ;
    ANTENNADIFFAREA 0.445500 ;
    PORT
      LAYER met3 ;
        RECT 387.775 326.440 391.775 327.040 ;
    END
  END y1[1]
  PIN y1[2]
    DIRECTION OUTPUT ;
    USE SIGNAL ;
    ANTENNADIFFAREA 0.445500 ;
    PORT
      LAYER met3 ;
        RECT 387.775 329.840 391.775 330.440 ;
    END
  END y1[2]
  PIN y1[3]
    DIRECTION OUTPUT ;
    USE SIGNAL ;
    ANTENNADIFFAREA 0.445500 ;
    PORT
      LAYER met3 ;
        RECT 387.775 340.040 391.775 340.640 ;
    END
  END y1[3]
  PIN y1[4]
    DIRECTION OUTPUT ;
    USE SIGNAL ;
    ANTENNADIFFAREA 0.445500 ;
    PORT
      LAYER met3 ;
        RECT 387.775 350.240 391.775 350.840 ;
    END
  END y1[4]
  PIN y1[5]
    DIRECTION OUTPUT ;
    USE SIGNAL ;
    ANTENNADIFFAREA 0.445500 ;
    PORT
      LAYER met3 ;
        RECT 387.775 346.840 391.775 347.440 ;
    END
  END y1[5]
  PIN y1[6]
    DIRECTION OUTPUT ;
    USE SIGNAL ;
    ANTENNADIFFAREA 0.445500 ;
    PORT
      LAYER met2 ;
        RECT 351.070 398.495 351.350 402.495 ;
    END
  END y1[6]
  PIN y1[7]
    DIRECTION OUTPUT ;
    USE SIGNAL ;
    ANTENNADIFFAREA 0.445500 ;
    PORT
      LAYER met2 ;
        RECT 341.410 398.495 341.690 402.495 ;
    END
  END y1[7]
  PIN y1[8]
    DIRECTION OUTPUT ;
    USE SIGNAL ;
    ANTENNADIFFAREA 0.445500 ;
    PORT
      LAYER met2 ;
        RECT 318.870 398.495 319.150 402.495 ;
    END
  END y1[8]
  PIN y1[9]
    DIRECTION OUTPUT ;
    USE SIGNAL ;
    ANTENNADIFFAREA 0.445500 ;
    PORT
      LAYER met2 ;
        RECT 315.650 398.495 315.930 402.495 ;
    END
  END y1[9]
  PIN y2[0]
    DIRECTION OUTPUT ;
    USE SIGNAL ;
    ANTENNADIFFAREA 0.445500 ;
    PORT
      LAYER met3 ;
        RECT 387.775 85.040 391.775 85.640 ;
    END
  END y2[0]
  PIN y2[10]
    DIRECTION OUTPUT ;
    USE SIGNAL ;
    ANTENNADIFFAREA 0.445500 ;
    PORT
      LAYER met2 ;
        RECT 322.090 0.000 322.370 4.000 ;
    END
  END y2[10]
  PIN y2[11]
    DIRECTION OUTPUT ;
    USE SIGNAL ;
    ANTENNADIFFAREA 0.445500 ;
    PORT
      LAYER met2 ;
        RECT 312.430 0.000 312.710 4.000 ;
    END
  END y2[11]
  PIN y2[12]
    DIRECTION OUTPUT ;
    USE SIGNAL ;
    ANTENNADIFFAREA 0.445500 ;
    PORT
      LAYER met2 ;
        RECT 325.310 0.000 325.590 4.000 ;
    END
  END y2[12]
  PIN y2[13]
    DIRECTION OUTPUT ;
    USE SIGNAL ;
    ANTENNADIFFAREA 0.445500 ;
    PORT
      LAYER met2 ;
        RECT 202.950 0.000 203.230 4.000 ;
    END
  END y2[13]
  PIN y2[14]
    DIRECTION OUTPUT ;
    USE SIGNAL ;
    ANTENNADIFFAREA 0.445500 ;
    PORT
      LAYER met2 ;
        RECT 193.290 0.000 193.570 4.000 ;
    END
  END y2[14]
  PIN y2[15]
    DIRECTION OUTPUT ;
    USE SIGNAL ;
    ANTENNADIFFAREA 0.445500 ;
    PORT
      LAYER met2 ;
        RECT 164.310 0.000 164.590 4.000 ;
    END
  END y2[15]
  PIN y2[16]
    DIRECTION OUTPUT ;
    USE SIGNAL ;
    ANTENNADIFFAREA 0.445500 ;
    PORT
      LAYER met2 ;
        RECT 135.330 0.000 135.610 4.000 ;
    END
  END y2[16]
  PIN y2[1]
    DIRECTION OUTPUT ;
    USE SIGNAL ;
    ANTENNADIFFAREA 0.445500 ;
    PORT
      LAYER met3 ;
        RECT 387.775 81.640 391.775 82.240 ;
    END
  END y2[1]
  PIN y2[2]
    DIRECTION OUTPUT ;
    USE SIGNAL ;
    ANTENNADIFFAREA 0.445500 ;
    PORT
      LAYER met3 ;
        RECT 387.775 78.240 391.775 78.840 ;
    END
  END y2[2]
  PIN y2[3]
    DIRECTION OUTPUT ;
    USE SIGNAL ;
    ANTENNADIFFAREA 0.445500 ;
    PORT
      LAYER met3 ;
        RECT 387.775 74.840 391.775 75.440 ;
    END
  END y2[3]
  PIN y2[4]
    DIRECTION OUTPUT ;
    USE SIGNAL ;
    ANTENNADIFFAREA 0.445500 ;
    PORT
      LAYER met3 ;
        RECT 387.775 54.440 391.775 55.040 ;
    END
  END y2[4]
  PIN y2[5]
    DIRECTION OUTPUT ;
    USE SIGNAL ;
    ANTENNADIFFAREA 0.445500 ;
    PORT
      LAYER met3 ;
        RECT 387.775 51.040 391.775 51.640 ;
    END
  END y2[5]
  PIN y2[6]
    DIRECTION OUTPUT ;
    USE SIGNAL ;
    ANTENNADIFFAREA 0.445500 ;
    PORT
      LAYER met3 ;
        RECT 387.775 44.240 391.775 44.840 ;
    END
  END y2[6]
  PIN y2[7]
    DIRECTION OUTPUT ;
    USE SIGNAL ;
    ANTENNADIFFAREA 0.445500 ;
    PORT
      LAYER met2 ;
        RECT 351.070 0.000 351.350 4.000 ;
    END
  END y2[7]
  PIN y2[8]
    DIRECTION OUTPUT ;
    USE SIGNAL ;
    ANTENNADIFFAREA 0.445500 ;
    PORT
      LAYER met2 ;
        RECT 344.630 0.000 344.910 4.000 ;
    END
  END y2[8]
  PIN y2[9]
    DIRECTION OUTPUT ;
    USE SIGNAL ;
    ANTENNADIFFAREA 0.445500 ;
    PORT
      LAYER met2 ;
        RECT 338.190 0.000 338.470 4.000 ;
    END
  END y2[9]
  PIN y3[0]
    DIRECTION OUTPUT ;
    USE SIGNAL ;
    ANTENNADIFFAREA 0.445500 ;
    PORT
      LAYER met3 ;
        RECT 387.775 193.840 391.775 194.440 ;
    END
  END y3[0]
  PIN y3[10]
    DIRECTION OUTPUT ;
    USE SIGNAL ;
    ANTENNADIFFAREA 0.445500 ;
    PORT
      LAYER met3 ;
        RECT 387.775 119.040 391.775 119.640 ;
    END
  END y3[10]
  PIN y3[11]
    DIRECTION OUTPUT ;
    USE SIGNAL ;
    ANTENNADIFFAREA 0.445500 ;
    PORT
      LAYER met3 ;
        RECT 387.775 115.640 391.775 116.240 ;
    END
  END y3[11]
  PIN y3[12]
    DIRECTION OUTPUT ;
    USE SIGNAL ;
    ANTENNADIFFAREA 0.445500 ;
    PORT
      LAYER met3 ;
        RECT 387.775 125.840 391.775 126.440 ;
    END
  END y3[12]
  PIN y3[13]
    DIRECTION OUTPUT ;
    USE SIGNAL ;
    ANTENNADIFFAREA 0.445500 ;
    PORT
      LAYER met2 ;
        RECT 199.730 0.000 200.010 4.000 ;
    END
  END y3[13]
  PIN y3[14]
    DIRECTION OUTPUT ;
    USE SIGNAL ;
    ANTENNADIFFAREA 0.445500 ;
    PORT
      LAYER met2 ;
        RECT 186.850 0.000 187.130 4.000 ;
    END
  END y3[14]
  PIN y3[15]
    DIRECTION OUTPUT ;
    USE SIGNAL ;
    ANTENNADIFFAREA 0.445500 ;
    PORT
      LAYER met2 ;
        RECT 177.190 0.000 177.470 4.000 ;
    END
  END y3[15]
  PIN y3[16]
    DIRECTION OUTPUT ;
    USE SIGNAL ;
    ANTENNADIFFAREA 0.445500 ;
    PORT
      LAYER met2 ;
        RECT 161.090 0.000 161.370 4.000 ;
    END
  END y3[16]
  PIN y3[1]
    DIRECTION OUTPUT ;
    USE SIGNAL ;
    ANTENNADIFFAREA 0.445500 ;
    PORT
      LAYER met3 ;
        RECT 387.775 190.440 391.775 191.040 ;
    END
  END y3[1]
  PIN y3[2]
    DIRECTION OUTPUT ;
    USE SIGNAL ;
    ANTENNADIFFAREA 0.445500 ;
    PORT
      LAYER met3 ;
        RECT 387.775 187.040 391.775 187.640 ;
    END
  END y3[2]
  PIN y3[3]
    DIRECTION OUTPUT ;
    USE SIGNAL ;
    ANTENNADIFFAREA 0.445500 ;
    PORT
      LAYER met3 ;
        RECT 387.775 176.840 391.775 177.440 ;
    END
  END y3[3]
  PIN y3[4]
    DIRECTION OUTPUT ;
    USE SIGNAL ;
    ANTENNADIFFAREA 0.445500 ;
    PORT
      LAYER met3 ;
        RECT 387.775 173.440 391.775 174.040 ;
    END
  END y3[4]
  PIN y3[5]
    DIRECTION OUTPUT ;
    USE SIGNAL ;
    ANTENNADIFFAREA 0.445500 ;
    PORT
      LAYER met3 ;
        RECT 387.775 166.640 391.775 167.240 ;
    END
  END y3[5]
  PIN y3[6]
    DIRECTION OUTPUT ;
    USE SIGNAL ;
    ANTENNADIFFAREA 0.445500 ;
    PORT
      LAYER met3 ;
        RECT 387.775 156.440 391.775 157.040 ;
    END
  END y3[6]
  PIN y3[7]
    DIRECTION OUTPUT ;
    USE SIGNAL ;
    ANTENNADIFFAREA 0.445500 ;
    PORT
      LAYER met3 ;
        RECT 387.775 146.240 391.775 146.840 ;
    END
  END y3[7]
  PIN y3[8]
    DIRECTION OUTPUT ;
    USE SIGNAL ;
    ANTENNADIFFAREA 0.445500 ;
    PORT
      LAYER met3 ;
        RECT 387.775 136.040 391.775 136.640 ;
    END
  END y3[8]
  PIN y3[9]
    DIRECTION OUTPUT ;
    USE SIGNAL ;
    ANTENNADIFFAREA 0.445500 ;
    PORT
      LAYER met3 ;
        RECT 387.775 132.640 391.775 133.240 ;
    END
  END y3[9]
  OBS
      LAYER nwell ;
        RECT 5.330 10.795 386.130 389.150 ;
      LAYER li1 ;
        RECT 5.520 10.795 385.940 389.045 ;
      LAYER met1 ;
        RECT 4.210 0.380 386.240 389.940 ;
      LAYER met2 ;
        RECT 4.230 398.215 135.050 398.890 ;
        RECT 135.890 398.215 138.270 398.890 ;
        RECT 139.110 398.215 141.490 398.890 ;
        RECT 142.330 398.215 144.710 398.890 ;
        RECT 145.550 398.215 147.930 398.890 ;
        RECT 148.770 398.215 151.150 398.890 ;
        RECT 151.990 398.215 154.370 398.890 ;
        RECT 155.210 398.215 173.690 398.890 ;
        RECT 174.530 398.215 193.010 398.890 ;
        RECT 193.850 398.215 196.230 398.890 ;
        RECT 197.070 398.215 199.450 398.890 ;
        RECT 200.290 398.215 202.670 398.890 ;
        RECT 203.510 398.215 205.890 398.890 ;
        RECT 206.730 398.215 209.110 398.890 ;
        RECT 209.950 398.215 212.330 398.890 ;
        RECT 213.170 398.215 215.550 398.890 ;
        RECT 216.390 398.215 218.770 398.890 ;
        RECT 219.610 398.215 221.990 398.890 ;
        RECT 222.830 398.215 225.210 398.890 ;
        RECT 226.050 398.215 228.430 398.890 ;
        RECT 229.270 398.215 231.650 398.890 ;
        RECT 232.490 398.215 234.870 398.890 ;
        RECT 235.710 398.215 238.090 398.890 ;
        RECT 238.930 398.215 241.310 398.890 ;
        RECT 242.150 398.215 244.530 398.890 ;
        RECT 245.370 398.215 247.750 398.890 ;
        RECT 248.590 398.215 250.970 398.890 ;
        RECT 251.810 398.215 254.190 398.890 ;
        RECT 255.030 398.215 257.410 398.890 ;
        RECT 258.250 398.215 260.630 398.890 ;
        RECT 261.470 398.215 263.850 398.890 ;
        RECT 264.690 398.215 267.070 398.890 ;
        RECT 267.910 398.215 270.290 398.890 ;
        RECT 271.130 398.215 273.510 398.890 ;
        RECT 274.350 398.215 276.730 398.890 ;
        RECT 277.570 398.215 279.950 398.890 ;
        RECT 280.790 398.215 283.170 398.890 ;
        RECT 284.010 398.215 286.390 398.890 ;
        RECT 287.230 398.215 289.610 398.890 ;
        RECT 290.450 398.215 292.830 398.890 ;
        RECT 293.670 398.215 296.050 398.890 ;
        RECT 296.890 398.215 299.270 398.890 ;
        RECT 300.110 398.215 302.490 398.890 ;
        RECT 303.330 398.215 305.710 398.890 ;
        RECT 306.550 398.215 308.930 398.890 ;
        RECT 309.770 398.215 312.150 398.890 ;
        RECT 312.990 398.215 315.370 398.890 ;
        RECT 316.210 398.215 318.590 398.890 ;
        RECT 319.430 398.215 321.810 398.890 ;
        RECT 322.650 398.215 325.030 398.890 ;
        RECT 325.870 398.215 328.250 398.890 ;
        RECT 329.090 398.215 331.470 398.890 ;
        RECT 332.310 398.215 334.690 398.890 ;
        RECT 335.530 398.215 341.130 398.890 ;
        RECT 341.970 398.215 350.790 398.890 ;
        RECT 351.630 398.215 384.920 398.890 ;
        RECT 4.230 4.280 384.920 398.215 ;
        RECT 4.230 0.350 41.670 4.280 ;
        RECT 42.510 0.350 44.890 4.280 ;
        RECT 45.730 0.350 48.110 4.280 ;
        RECT 48.950 0.350 70.650 4.280 ;
        RECT 71.490 0.350 73.870 4.280 ;
        RECT 74.710 0.350 77.090 4.280 ;
        RECT 77.930 0.350 80.310 4.280 ;
        RECT 81.150 0.350 83.530 4.280 ;
        RECT 84.370 0.350 86.750 4.280 ;
        RECT 87.590 0.350 89.970 4.280 ;
        RECT 90.810 0.350 93.190 4.280 ;
        RECT 94.030 0.350 96.410 4.280 ;
        RECT 97.250 0.350 99.630 4.280 ;
        RECT 100.470 0.350 102.850 4.280 ;
        RECT 103.690 0.350 106.070 4.280 ;
        RECT 106.910 0.350 109.290 4.280 ;
        RECT 110.130 0.350 112.510 4.280 ;
        RECT 113.350 0.350 115.730 4.280 ;
        RECT 116.570 0.350 118.950 4.280 ;
        RECT 119.790 0.350 122.170 4.280 ;
        RECT 123.010 0.350 125.390 4.280 ;
        RECT 126.230 0.350 128.610 4.280 ;
        RECT 129.450 0.350 131.830 4.280 ;
        RECT 132.670 0.350 135.050 4.280 ;
        RECT 135.890 0.350 138.270 4.280 ;
        RECT 139.110 0.350 141.490 4.280 ;
        RECT 142.330 0.350 144.710 4.280 ;
        RECT 145.550 0.350 147.930 4.280 ;
        RECT 148.770 0.350 151.150 4.280 ;
        RECT 151.990 0.350 154.370 4.280 ;
        RECT 155.210 0.350 157.590 4.280 ;
        RECT 158.430 0.350 160.810 4.280 ;
        RECT 161.650 0.350 164.030 4.280 ;
        RECT 164.870 0.350 167.250 4.280 ;
        RECT 168.090 0.350 170.470 4.280 ;
        RECT 171.310 0.350 173.690 4.280 ;
        RECT 174.530 0.350 176.910 4.280 ;
        RECT 177.750 0.350 180.130 4.280 ;
        RECT 180.970 0.350 183.350 4.280 ;
        RECT 184.190 0.350 186.570 4.280 ;
        RECT 187.410 0.350 189.790 4.280 ;
        RECT 190.630 0.350 193.010 4.280 ;
        RECT 193.850 0.350 196.230 4.280 ;
        RECT 197.070 0.350 199.450 4.280 ;
        RECT 200.290 0.350 202.670 4.280 ;
        RECT 203.510 0.350 205.890 4.280 ;
        RECT 206.730 0.350 209.110 4.280 ;
        RECT 209.950 0.350 212.330 4.280 ;
        RECT 213.170 0.350 215.550 4.280 ;
        RECT 216.390 0.350 218.770 4.280 ;
        RECT 219.610 0.350 221.990 4.280 ;
        RECT 222.830 0.350 225.210 4.280 ;
        RECT 226.050 0.350 228.430 4.280 ;
        RECT 229.270 0.350 231.650 4.280 ;
        RECT 232.490 0.350 234.870 4.280 ;
        RECT 235.710 0.350 238.090 4.280 ;
        RECT 238.930 0.350 241.310 4.280 ;
        RECT 242.150 0.350 244.530 4.280 ;
        RECT 245.370 0.350 247.750 4.280 ;
        RECT 248.590 0.350 250.970 4.280 ;
        RECT 251.810 0.350 254.190 4.280 ;
        RECT 255.030 0.350 257.410 4.280 ;
        RECT 258.250 0.350 260.630 4.280 ;
        RECT 261.470 0.350 263.850 4.280 ;
        RECT 264.690 0.350 267.070 4.280 ;
        RECT 267.910 0.350 270.290 4.280 ;
        RECT 271.130 0.350 276.730 4.280 ;
        RECT 277.570 0.350 312.150 4.280 ;
        RECT 312.990 0.350 321.810 4.280 ;
        RECT 322.650 0.350 325.030 4.280 ;
        RECT 325.870 0.350 337.910 4.280 ;
        RECT 338.750 0.350 344.350 4.280 ;
        RECT 345.190 0.350 350.790 4.280 ;
        RECT 351.630 0.350 384.920 4.280 ;
      LAYER met3 ;
        RECT 3.990 351.240 387.775 389.125 ;
        RECT 3.990 349.840 387.375 351.240 ;
        RECT 3.990 347.840 387.775 349.840 ;
        RECT 3.990 346.440 387.375 347.840 ;
        RECT 3.990 341.040 387.775 346.440 ;
        RECT 3.990 339.640 387.375 341.040 ;
        RECT 3.990 330.840 387.775 339.640 ;
        RECT 3.990 329.440 387.375 330.840 ;
        RECT 3.990 327.440 387.775 329.440 ;
        RECT 3.990 326.040 387.375 327.440 ;
        RECT 3.990 320.640 387.775 326.040 ;
        RECT 4.400 319.240 387.375 320.640 ;
        RECT 3.990 317.240 387.775 319.240 ;
        RECT 4.400 315.840 387.775 317.240 ;
        RECT 3.990 313.840 387.775 315.840 ;
        RECT 4.400 312.440 387.775 313.840 ;
        RECT 3.990 300.240 387.775 312.440 ;
        RECT 4.400 298.840 387.775 300.240 ;
        RECT 3.990 293.440 387.775 298.840 ;
        RECT 4.400 292.040 387.775 293.440 ;
        RECT 3.990 290.040 387.775 292.040 ;
        RECT 4.400 288.640 387.775 290.040 ;
        RECT 3.990 286.640 387.775 288.640 ;
        RECT 4.400 285.240 387.375 286.640 ;
        RECT 3.990 283.240 387.775 285.240 ;
        RECT 4.400 281.840 387.375 283.240 ;
        RECT 3.990 279.840 387.775 281.840 ;
        RECT 4.400 278.440 387.375 279.840 ;
        RECT 3.990 276.440 387.775 278.440 ;
        RECT 4.400 275.040 387.375 276.440 ;
        RECT 3.990 273.040 387.775 275.040 ;
        RECT 3.990 271.640 387.375 273.040 ;
        RECT 3.990 269.640 387.775 271.640 ;
        RECT 3.990 268.240 387.375 269.640 ;
        RECT 3.990 266.240 387.775 268.240 ;
        RECT 3.990 264.840 387.375 266.240 ;
        RECT 3.990 262.840 387.775 264.840 ;
        RECT 3.990 261.440 387.375 262.840 ;
        RECT 3.990 259.440 387.775 261.440 ;
        RECT 3.990 258.040 387.375 259.440 ;
        RECT 3.990 256.040 387.775 258.040 ;
        RECT 3.990 254.640 387.375 256.040 ;
        RECT 3.990 252.640 387.775 254.640 ;
        RECT 4.400 251.240 387.375 252.640 ;
        RECT 3.990 249.240 387.775 251.240 ;
        RECT 4.400 247.840 387.375 249.240 ;
        RECT 3.990 245.840 387.775 247.840 ;
        RECT 4.400 244.440 387.375 245.840 ;
        RECT 3.990 242.440 387.775 244.440 ;
        RECT 3.990 241.040 387.375 242.440 ;
        RECT 3.990 239.040 387.775 241.040 ;
        RECT 3.990 237.640 387.375 239.040 ;
        RECT 3.990 235.640 387.775 237.640 ;
        RECT 3.990 234.240 387.375 235.640 ;
        RECT 3.990 232.240 387.775 234.240 ;
        RECT 4.400 230.840 387.375 232.240 ;
        RECT 3.990 228.840 387.775 230.840 ;
        RECT 4.400 227.440 387.375 228.840 ;
        RECT 3.990 225.440 387.775 227.440 ;
        RECT 4.400 224.040 387.375 225.440 ;
        RECT 3.990 222.040 387.775 224.040 ;
        RECT 4.400 220.640 387.375 222.040 ;
        RECT 3.990 218.640 387.775 220.640 ;
        RECT 3.990 217.240 387.375 218.640 ;
        RECT 3.990 215.240 387.775 217.240 ;
        RECT 4.400 213.840 387.375 215.240 ;
        RECT 3.990 211.840 387.775 213.840 ;
        RECT 4.400 210.440 387.375 211.840 ;
        RECT 3.990 208.440 387.775 210.440 ;
        RECT 4.400 207.040 387.375 208.440 ;
        RECT 3.990 205.040 387.775 207.040 ;
        RECT 4.400 203.640 387.375 205.040 ;
        RECT 3.990 201.640 387.775 203.640 ;
        RECT 4.400 200.240 387.375 201.640 ;
        RECT 3.990 198.240 387.775 200.240 ;
        RECT 4.400 196.840 387.375 198.240 ;
        RECT 3.990 194.840 387.775 196.840 ;
        RECT 4.400 193.440 387.375 194.840 ;
        RECT 3.990 191.440 387.775 193.440 ;
        RECT 4.400 190.040 387.375 191.440 ;
        RECT 3.990 188.040 387.775 190.040 ;
        RECT 4.400 186.640 387.375 188.040 ;
        RECT 3.990 184.640 387.775 186.640 ;
        RECT 4.400 183.240 387.375 184.640 ;
        RECT 3.990 181.240 387.775 183.240 ;
        RECT 4.400 179.840 387.375 181.240 ;
        RECT 3.990 177.840 387.775 179.840 ;
        RECT 4.400 176.440 387.375 177.840 ;
        RECT 3.990 174.440 387.775 176.440 ;
        RECT 4.400 173.040 387.375 174.440 ;
        RECT 3.990 171.040 387.775 173.040 ;
        RECT 4.400 169.640 387.375 171.040 ;
        RECT 3.990 167.640 387.775 169.640 ;
        RECT 3.990 166.240 387.375 167.640 ;
        RECT 3.990 164.240 387.775 166.240 ;
        RECT 3.990 162.840 387.375 164.240 ;
        RECT 3.990 160.840 387.775 162.840 ;
        RECT 4.400 159.440 387.375 160.840 ;
        RECT 3.990 157.440 387.775 159.440 ;
        RECT 3.990 156.040 387.375 157.440 ;
        RECT 3.990 154.040 387.775 156.040 ;
        RECT 3.990 152.640 387.375 154.040 ;
        RECT 3.990 150.640 387.775 152.640 ;
        RECT 4.400 149.240 387.375 150.640 ;
        RECT 3.990 147.240 387.775 149.240 ;
        RECT 3.990 145.840 387.375 147.240 ;
        RECT 3.990 143.840 387.775 145.840 ;
        RECT 3.990 142.440 387.375 143.840 ;
        RECT 3.990 140.440 387.775 142.440 ;
        RECT 3.990 139.040 387.375 140.440 ;
        RECT 3.990 137.040 387.775 139.040 ;
        RECT 3.990 135.640 387.375 137.040 ;
        RECT 3.990 133.640 387.775 135.640 ;
        RECT 3.990 132.240 387.375 133.640 ;
        RECT 3.990 126.840 387.775 132.240 ;
        RECT 3.990 125.440 387.375 126.840 ;
        RECT 3.990 123.440 387.775 125.440 ;
        RECT 3.990 122.040 387.375 123.440 ;
        RECT 3.990 120.040 387.775 122.040 ;
        RECT 3.990 118.640 387.375 120.040 ;
        RECT 3.990 116.640 387.775 118.640 ;
        RECT 3.990 115.240 387.375 116.640 ;
        RECT 3.990 106.440 387.775 115.240 ;
        RECT 3.990 105.040 387.375 106.440 ;
        RECT 3.990 103.040 387.775 105.040 ;
        RECT 3.990 101.640 387.375 103.040 ;
        RECT 3.990 99.640 387.775 101.640 ;
        RECT 3.990 98.240 387.375 99.640 ;
        RECT 3.990 96.240 387.775 98.240 ;
        RECT 3.990 94.840 387.375 96.240 ;
        RECT 3.990 92.840 387.775 94.840 ;
        RECT 3.990 91.440 387.375 92.840 ;
        RECT 3.990 89.440 387.775 91.440 ;
        RECT 3.990 88.040 387.375 89.440 ;
        RECT 3.990 86.040 387.775 88.040 ;
        RECT 3.990 84.640 387.375 86.040 ;
        RECT 3.990 82.640 387.775 84.640 ;
        RECT 3.990 81.240 387.375 82.640 ;
        RECT 3.990 79.240 387.775 81.240 ;
        RECT 3.990 77.840 387.375 79.240 ;
        RECT 3.990 75.840 387.775 77.840 ;
        RECT 3.990 74.440 387.375 75.840 ;
        RECT 3.990 55.440 387.775 74.440 ;
        RECT 3.990 54.040 387.375 55.440 ;
        RECT 3.990 52.040 387.775 54.040 ;
        RECT 3.990 50.640 387.375 52.040 ;
        RECT 3.990 45.240 387.775 50.640 ;
        RECT 3.990 43.840 387.375 45.240 ;
        RECT 3.990 7.655 387.775 43.840 ;
      LAYER met4 ;
        RECT 46.790 13.095 174.240 384.705 ;
        RECT 176.640 13.095 177.540 384.705 ;
        RECT 179.940 13.095 327.840 384.705 ;
        RECT 330.240 13.095 331.140 384.705 ;
        RECT 333.540 13.095 337.345 384.705 ;
      LAYER met5 ;
        RECT 46.580 33.230 242.300 152.100 ;
        RECT 46.580 17.900 242.300 25.130 ;
  END
END synth_top
END LIBRARY

